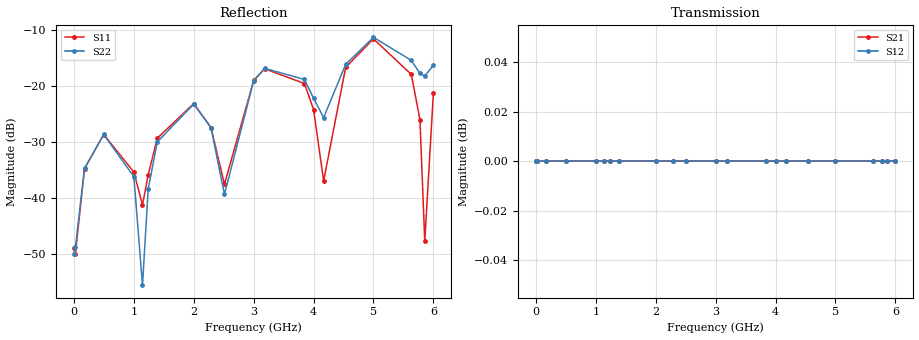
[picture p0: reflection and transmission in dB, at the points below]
!Agilent Technologies,M9375A,MY55441453,A.02.50.04
!Agilent M9375A: A.02.50.04
!Date: Monday, December 12, 2016 11:24:06
!Correction: S11(Full 2 Port(1,2))
!S21(Full 2 Port(1,2))
!S12(Full 2 Port(1,2))
!S22(Full 2 Port(1,2))
!S2P File: Measurements: S11, S21, S12, S22:
# Hz S  dB  R 50
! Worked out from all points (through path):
!   751 points, 300 kHz to 6 GHz, reference 50 ohm
!   highest |S21| = 0.00 dB at 3.184 GHz (marker M1); lowest = 0.0 dB at 3.848 GHz (marker M2)
!   lowest |S11| = -50.0 dB at 24.3 MHz (marker M3), VSWR 1.01, Z = 50.2 + j0.266 ohm
!   |S11| at or under -10 dB: start of sweep to end of sweep
!   |S22| runs from -55.9 to -11.2 dB; largest |S21 - S12| = 0.0027
!   S11 on the Smith chart (normalised r, x): 300 kHz: 0.99, -0.00; 4.536 GHz: 0.91, -0.27; 6 GHz: 1.00, +0.17
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300000  -48.98 -135.4  0.00 0.0  0.00 0.0  -49.96 -172.4
2.42988e7  -49.99 56.8  0.00 0.0  0.00 -0.0  -48.77 54.5
1.762912e8  -34.78 80.7  0.00 0.0  0.00 -0.0  -34.72 80.3
4.962752e8  -28.69 90.2  0.00 0.0  0.00 -0.0  -28.68 85.9
1.00025e9  -35.37 115.6  0.00 0.0  0.00 -0.0  -36.20 85.3
1.144243e9  -41.21 -171.9  -0.00 0.0  0.00 -0.0  -55.52 -26.5
1.240238e9  -35.83 -128.4  0.00 0.0  0.00 -0.0  -38.33 -84.9
1.39223e9  -29.33 -108.0  -0.00 0.0  0.00 -0.0  -29.99 -87.8
2.0002e9  -23.17 -93.2  0.00 0.0  0.00 -0.0  -23.26 -84.8
2.288186e9  -27.44 -82.5  0.00 0.0  0.00 -0.1  -27.49 -75.8
2.512174e9  -37.55 -2.6  0.00 0.0  0.00 -0.1  -39.35 5.0
3.00015e9  -19.06 79.1  0.00 0.0  0.00 -0.1  -19.10 90.7
3.184141e9  -16.98 81.7  0.00 0.0  0.00 -0.1  -16.90 94.3
3.848108e9  -19.60 89.8  -0.00 0.0  0.00 -0.1  -18.88 113.9
4.0001e9  -24.25 96.2  -0.00 0.0  0.00 -0.1  -22.22 130.8
4.168092e9  -36.94 177.0  0.00 0.0  0.00 -0.0  -25.67 -176.4
4.536073e9  -16.71 -100.6  0.00 0.0  0.00 -0.1  -16.17 -103.4
5.00005e9  -11.65 -96.2  -0.00 0.0  0.00 -0.1  -11.38 -85.5
5.632018e9  -17.98 -92.3  0.00 0.0  0.00 -0.1  -15.47 -49.7
5.776011e9  -26.08 -90.1  0.00 0.0  0.00 -0.1  -17.81 -22.6
5.856007e9  -47.72 -44.5  0.00 0.0  0.00 -0.1  -18.23 0.0
6e9  -21.32 85.6  0.00 0.0  0.00 -0.1  -16.38 37.1
